VERSION 5.7 ;
  NOWIREEXTENSIONATPIN ON ;
  DIVIDERCHAR "/" ;
  BUSBITCHARS "[]" ;
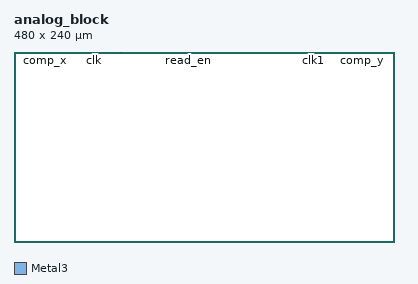
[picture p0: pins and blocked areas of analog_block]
MACRO analog_block
  CLASS BLOCK ;
  FOREIGN analog_block ;
  ORIGIN 0.000 0.000 ;
  SIZE 480.000 BY 240.000 ;

  PIN comp_x
    DIRECTION OUTPUT ;
    USE SIGNAL ;
    PORT
      LAYER Metal3 ;
        RECT 39.56 239.72 39.84 240 ;
    END
  END comp_x

  PIN clk
    DIRECTION INPUT ;
    USE SIGNAL ;
    PORT
      LAYER Metal3 ;
        RECT 101.24 239.72 101.52 240 ;
    END
  END clk

  PIN ref_wave_x
    DIRECTION INPUT ;
    USE SIGNAL ;
    PORT
      LAYER Metal3 ;
        RECT 135 239.72 135.28 240 ;
    END
  END ref_wave_x

  PIN read_en
    DIRECTION INPUT ;
    USE SIGNAL ;
    PORT
      LAYER Metal3 ;
        RECT 219.72 239.72 220 240 ;
    END
  END read_en

  PIN ref_wave_y
    DIRECTION INPUT ;
    USE SIGNAL ;
    PORT
      LAYER Metal3 ;
        RECT 345 239.72 345.28 240 ;
    END
  END ref_wave_y

  PIN clk1
    DIRECTION INPUT ;
    USE SIGNAL ;
    PORT
      LAYER Metal3 ;
        RECT 378.48 239.72 378.76 240 ;
    END
  END clk1

  PIN comp_y
    DIRECTION OUTPUT ;
    USE SIGNAL ;
    PORT
      LAYER Metal3 ;
        RECT 440.16 239.72 440.44 240 ;
    END
  END comp_y

END analog_block
END LIBRARY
